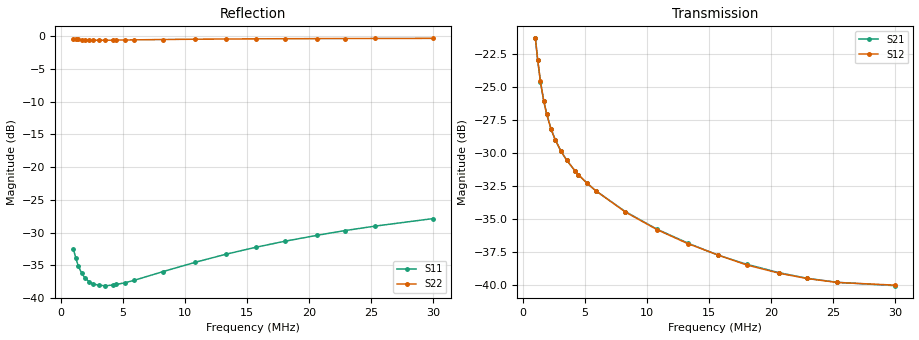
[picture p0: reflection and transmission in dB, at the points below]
! ListType=Log
!!FT140-43 7T RG174
# MHZ S RI R 50
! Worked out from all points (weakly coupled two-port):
!   101 points, 1 MHz to 30 MHz, reference 50 ohm
!   highest |S21| = -21.33 dB at 1 MHz (marker M1); lowest = -40.0 dB at 30 MHz (marker M2)
!   lowest |S11| = -38.1 dB at 3.52 MHz (marker M3), VSWR 1.03, Z = 49.8 + j1.21 ohm
!   |S11| at or under -10 dB: start of sweep to end of sweep
!   |S22| runs from -0.6 to -0.3 dB; largest |S21 - S12| = 0.00025
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1  -0.00586 0.0229  0.0265 -0.0816  0.0265 -0.0817  0.8898 0.325
1.185376  -0.0046 0.0197  0.0219 -0.0674  0.0219 -0.0676  0.9085 0.2681
1.405116  -0.00388 0.017  0.0198 -0.0555  0.0198 -0.0556  0.9171 0.2199
1.66559  -0.00358 0.015  0.0191 -0.0461  0.019 -0.0462  0.9202 0.1817
1.908328  -0.00345 0.0139  0.0189 -0.0402  0.0188 -0.0402  0.9211 0.1572
2.262086  -0.00317 0.0129  0.0187 -0.0342  0.0186 -0.0342  0.9218 0.1326
2.591755  -0.00299 0.0125  0.0185 -0.0304  0.0184 -0.0304  0.9225 0.1165
3.072204  -0.00262 0.0122  0.0181 -0.0265  0.0181 -0.0265  0.9239 0.0999
3.519937  -0.00231 0.0122  0.0177 -0.0239  0.0177 -0.0239  0.9254 0.0886
4.172448  -0.00188 0.0124  0.017 -0.0212  0.017 -0.0212  0.9279 0.0765
4.466151  -0.00163 0.0126  0.0167 -0.0202  0.0167 -0.0202  0.9291 0.072
5.117033  -0.0012 0.013  0.0161 -0.0184  0.0161 -0.0184  0.9315 0.0637
5.862773  -0.000651 0.0136  0.0154 -0.0168  0.0154 -0.0168  0.934 0.0558
8.237875  0.00103 0.0159  0.0136 -0.0133  0.0136 -0.0132  0.9408 0.0377
10.81396  0.00296 0.0185  0.0122 -0.0108  0.0122 -0.0107  0.9461 0.0235
13.2621  0.00489 0.021  0.0113 -0.00903  0.0113 -0.00892  0.9498 0.0123
15.72057  0.00703 0.0234  0.0106 -0.00754  0.0107 -0.00742  0.9526 0.00229
18.01163  0.00917 0.0255  0.0102 -0.00636  0.0102 -0.00622  0.9547 -0.00617
20.63659  0.0118 0.0277  0.0099 -0.00516  0.00993 -0.005  0.9563 -0.0153
22.85344  0.0141 0.0295  0.00975 -0.00427  0.0098 -0.00409  0.9574 -0.0226
25.30843  0.0169 0.0311  0.0097 -0.00338  0.00975 -0.00318  0.9583 -0.0302
30  0.0225 0.0336  0.00979 -0.0019  0.00988 -0.00166  0.9596 -0.0441
